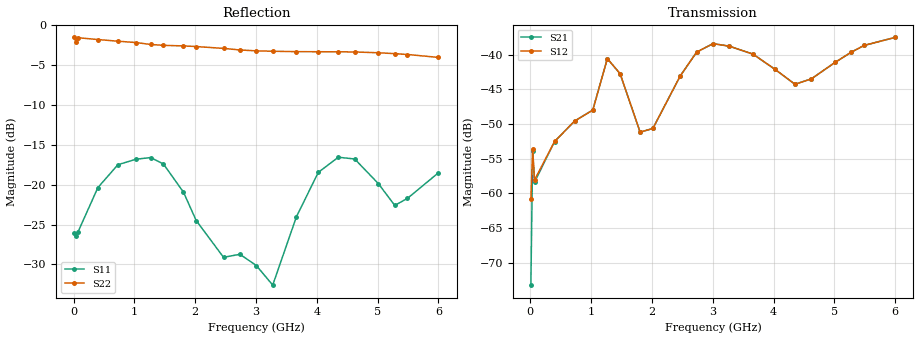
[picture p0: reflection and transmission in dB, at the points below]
!Agilent Technologies,E8364B,MY43040528,A.07.50.67
!Agilent E8364B: A.07.50.67
!Date: Sunday, September 28, 2025 22:28:29
!Correction: S11(Full 2 Port(1,2))
!S21(Full 2 Port(1,2))
!S12(Full 2 Port(1,2))
!S22(Full 2 Port(1,2))
!S2P File: Measurements: S11, S21, S12, S22:
# Hz S  dB  R 50
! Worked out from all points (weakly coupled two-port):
!   201 points, 10 MHz to 6 GHz, reference 50 ohm
!   highest |S21| = -37.51 dB at 6 GHz (marker M1); lowest = -73.2 dB at 10 MHz (marker M2)
!   lowest |S11| = -32.6 dB at 3.275 GHz (marker M3), VSWR 1.05, Z = 49.2 + j2.17 ohm
!   |S11| at or under -10 dB: start of sweep to end of sweep
!   |S22| runs from -4.0 to -1.5 dB; largest |S21 - S12| = 0.00077
!   S11 on the Smith chart (normalised r, x): 10 MHz: 1.09, -0.05; 728.8 MHz: 0.78, -0.09; 1.478 GHz: 0.87, +0.22; 4.622 GHz: 1.22, +0.24; 6 GHz: 1.24, -0.12
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1e7  -26.08 -25.6  -73.21 90.3  -60.85 44.9  -1.51 179.9
3.995e7  -26.38 -17.3  -53.84 19.2  -53.66 17.8  -2.09 -175.9
6.99e7  -25.97 -23.4  -58.39 14.1  -58.06 11.6  -1.55 174.6
3.9935e8  -20.36 -103.0  -52.53 3.8  -52.51 3.3  -1.78 133.4
7.288e8  -17.49 -155.8  -49.56 -37.3  -49.58 -37.5  -1.99 95.9
1.0283e9  -16.80 167.3  -47.97 -62.8  -47.99 -63.0  -2.16 61.5
1.2679e9  -16.59 139.3  -40.57 -113.6  -40.57 -113.6  -2.40 34.2
1.47755e9  -17.40 113.2  -42.76 162.2  -42.74 162.3  -2.51 11.4
1.807e9  -20.94 79.5  -51.18 69.0  -51.16 69.1  -2.58 -27.1
2.01665e9  -24.50 68.1  -50.63 -7.6  -50.63 -7.7  -2.66 -52.3
2.4659e9  -29.11 84.7  -43.08 -125.6  -43.07 -125.4  -2.89 -107.4
2.73545e9  -28.73 87.5  -39.64 -178.2  -39.64 -178.1  -3.09 -140.6
3.005e9  -30.14 86.0  -38.41 126.1  -38.41 126.1  -3.20 -173.5
3.27455e9  -32.60 109.6  -38.78 79.2  -38.78 79.4  -3.25 153.3
3.6639e9  -24.03 135.3  -39.93 21.3  -39.93 21.4  -3.30 106.1
4.0233e9  -18.46 104.4  -42.11 -26.0  -42.10 -25.9  -3.31 64.2
4.35275e9  -16.55 68.9  -44.26 -49.7  -44.27 -49.5  -3.32 27.1
4.6223e9  -16.77 40.6  -43.49 -65.7  -43.49 -65.6  -3.34 -2.9
5.01165e9  -19.86 9.7  -41.12 -103.8  -41.12 -103.8  -3.44 -46.3
5.2812e9  -22.60 10.8  -39.63 -136.9  -39.63 -136.8  -3.55 -76.8
5.49085e9  -21.71 18.1  -38.67 -165.2  -38.67 -165.1  -3.66 -100.7
6e9  -18.50 -24.2  -37.51 120.2  -37.51 120.4  -4.02 -161.0
